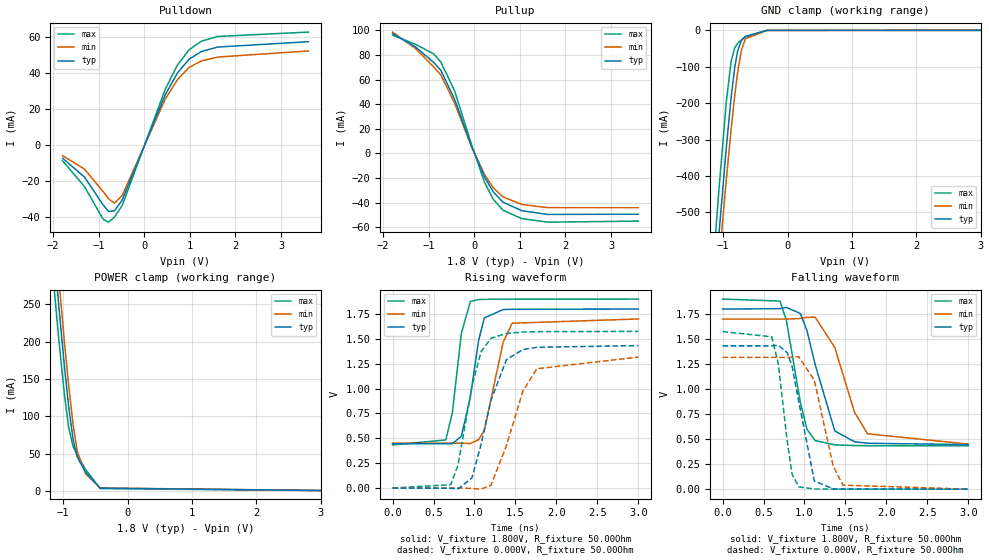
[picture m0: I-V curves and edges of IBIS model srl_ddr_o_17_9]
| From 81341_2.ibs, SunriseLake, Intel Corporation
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[Model]   srl_ddr_o_17_9
Model_type   Output
|Vinl = 650.000mV
|Vinh = 1.150V
Vmeas = 900.000mV
Vref = 900.000mV
Cref = 0.000F
Rref = 25.000Ohm
|   typ   min   max
C_comp   3.270pF   2.760pF   3.820pF
[Voltage Range]   1.800V   1.700V   1.900V
[Temperature Range]   60.0   110.0   -5.0
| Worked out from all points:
|   slope of the pulldown table from 0 to 0.27 V, typ, clamps not added: 15.8 ohm
|   slope of the pullup table from 0 to 0.27 V, typ, clamps not added: 12 ohm
|   GND clamp passes 1 mA (typ) near -0.41 V on its own axis
|   POWER clamp passes 1 mA (typ) near -0.35 V on its own axis
|   falling waveform, V_fixture 1.800V, R_fixture 50.00Ohm: 20-80 % time 245ps typ, 289ps min, 187ps max; typ from 1.8 V to 0.445 V
|   rising waveform, V_fixture 1.800V, R_fixture 50.00Ohm: 20-80 % time 151ps typ, 180ps min, 124ps max; typ from 0.445 V to 1.8 V
|   rising waveform, V_fixture 0.000V, R_fixture 50.00Ohm: 20-80 % time 259ps typ, 300ps min, 216ps max; typ from 0 V to 1.43 V
|   falling waveform, V_fixture 0.000V, R_fixture 50.00Ohm: 20-80 % time 175ps typ, 208ps min, 135ps max; typ from 1.43 V to 0 V
[Pulldown]
|   Voltage   I(typ)   I(min)   I(max)
-1.795V   -7.39mA    -5.975mA   -8.804mA
-1.315V   -17.83mA   -13.43mA   -23.1mA
-905mV    -33.28mA   -25.9mA    -41.28mA
-785mV    -36.99mA   -29.94mA   -42.92mA
-655mV    -36.57mA   -32.37mA   -40.11mA
-485mV    -30.56mA   -28mA      -33.56mA
455mV     27.6mA     25.21mA    30.63mA
725mV     39.87mA    36.24mA    44.26mA
980mV     47.53mA    42.95mA    52.77mA
1.25V     51.84mA    46.61mA    57.55mA
1.61V     54.32mA    48.78mA    60.21mA
3.6V      57.31mA    52.15mA    62.64mA
[GND Clamp]
|   Voltage   I(typ)   I(min)   I(max)
-1.795V   -2.204A    -2.188A    -2.214A
-1.165V   -777.4mA   -844.3mA   -670.1mA
-1.115V   -667.2mA   -740.5mA   -551.6mA
-1.07V    -569.4mA   -648mA     -447.4mA
-950mV    -320.2mA   -409.2mA   -194.4mA
-875mV    -182.6mA   -270.6mA   -84.27mA
-820mV    -101.8mA   -179.2mA   -47.93mA
-775mV    -57.03mA   -115.3mA   -35.76mA
-715mV    -27.68mA   -54mA      -25.89mA
-655mV    -16.67mA   -23.37mA   -18.05mA
-320mV    -113.3uA   -232.1uA   -24.81uA
3.6V      0A         0A         0A
[Pullup]
|   Voltage   I(typ)   I(min)   I(max)
-1.795V   97.29mA    98.53mA    96.09mA
-1.29V    86.5mA     85.19mA    88.61mA
-890mV    73.81mA    70.15mA    80.77mA
-735mV    67.5mA     63.79mA    74.17mA
-435mV    44.07mA    40.95mA    50.97mA
-65mV     6.251mA    5.666mA    7.632mA
225mV     -19.21mA   -17.2mA    -23.46mA
415mV     -31.18mA   -27.85mA   -37.27mA
630mV     -39.59mA   -35.33mA   -46.16mA
1.045V    -46.51mA   -41.44mA   -52.92mA
1.615V    -49.52mA   -44.04mA   -55.81mA
3.6V      -49.3mA    -44.06mA   -54.91mA
[POWER Clamp]
|   Voltage   I(typ)   I(min)   I(max)
-1.795V   1.029A     1.081A     953.5mA
-1.17V    349.9mA    389mA      300.6mA
-1.145V   324.6mA    363mA      276.3mA
-1.115V   294.4mA    332.1mA    247.5mA
-1.065V   245.4mA    281.6mA    201mA
-980mV    166.6mA    199.5mA    128.7mA
-915mV    113.2mA    141.8mA    85.32mA
-845mV    68.57mA    88.39mA    59.28mA
-780mV    45.17mA    52.7mA     47.98mA
-650mV    24.95mA    22.8mA     28.63mA
-425mV    3.719mA    3.953mA    3.218mA
3.6V      0A         0A         0A
[Ramp]
R_load = 50.00Ohm
|   typ   min   max
dV/dt_r   859.215mV/258.610ps 790.176mV/300.004ps 945.052mV/215.727ps
dV/dt_f   812.779mV/245.034ps 749.755mV/288.789ps 880.153mV/186.841ps
[Falling Waveform]
V_fixture = 1.800V
V_fixture_min = 1.700V
V_fixture_max = 1.900V
R_fixture = 50.00Ohm
|   Time   V(typ)   V(min)   V(max)
0s        1.8V       1.7V       1.9V
700ps     1.804V     1.7V       1.88V
780ps     1.816V     1.7V       1.683V
950ps     1.756V     1.706V     865.9mV
1.03ns    1.585V     1.717V     599.5mV
1.13ns    1.247V     1.719V     485.5mV
1.37ns    581.6mV    1.416V     443.2mV
1.61ns    473.6mV    770.5mV    435.9mV
1.77ns    459mV      553.3mV    434.3mV
3ns       445.4mV    450.4mV    433.1mV
[Rising Waveform]
V_fixture = 1.800V
V_fixture_min = 1.700V
V_fixture_max = 1.900V
R_fixture = 50.00Ohm
|   Time   V(typ)   V(min)   V(max)
0s        445.4mV    450.4mV    433.1mV
650ps     445.1mV    450.4mV    483.9mV
730ps     444.1mV    450.4mV    758.4mV
840ps     521.6mV    450.8mV    1.556V
950ps     917.5mV    447.1mV    1.876V
1.05ns    1.482V     486.9mV    1.895V
1.12ns    1.71V      578.7mV    1.897V
1.35ns    1.795V     1.466V     1.899V
1.46ns    1.797V     1.657V     1.899V
3ns       1.8V       1.7V       1.9V
[Rising Waveform]
V_fixture = 0.000V
V_fixture_min = 0.000V
V_fixture_max = 0.000V
R_fixture = 50.00Ohm
|   Time   V(typ)   V(min)   V(max)
0s        790.4nV    3.259uV    99.34nV
710ps     -2.464mV   -61.86uV   33.62mV
800ps     -9.696mV   558.6uV    235.1mV
970ps     102.9mV    -4.505mV   1.029V
1.08ns    437.7mV    -11.53mV   1.37V
1.2ns     879mV      26.84mV    1.505V
1.39ns    1.291V     426.3mV    1.554V
1.59ns    1.392V     971.7mV    1.568V
1.76ns    1.415V     1.199V     1.572V
3ns       1.432V     1.317V     1.575V
[Falling Waveform]
V_fixture = 0.000V
V_fixture_min = 0.000V
V_fixture_max = 0.000V
R_fixture = 50.00Ohm
|   Time   V(typ)   V(min)   V(max)
0s        1.432V     1.317V     1.575V
600ps     1.432V     1.317V     1.523V
680ps     1.438V     1.317V     1.255V
790ps     1.365V     1.317V     472.3mV
850ps     1.221V     1.317V     145.1mV
930ps     877.2mV    1.324V     22.83mV
1.12ns    81.62mV    1.089V     1.808mV
1.35ns    2.956mV    233.4mV    490.2uV
1.47ns    1.435mV    40.19mV    262.1uV
3ns       790.4nV    3.259uV    99.34nV
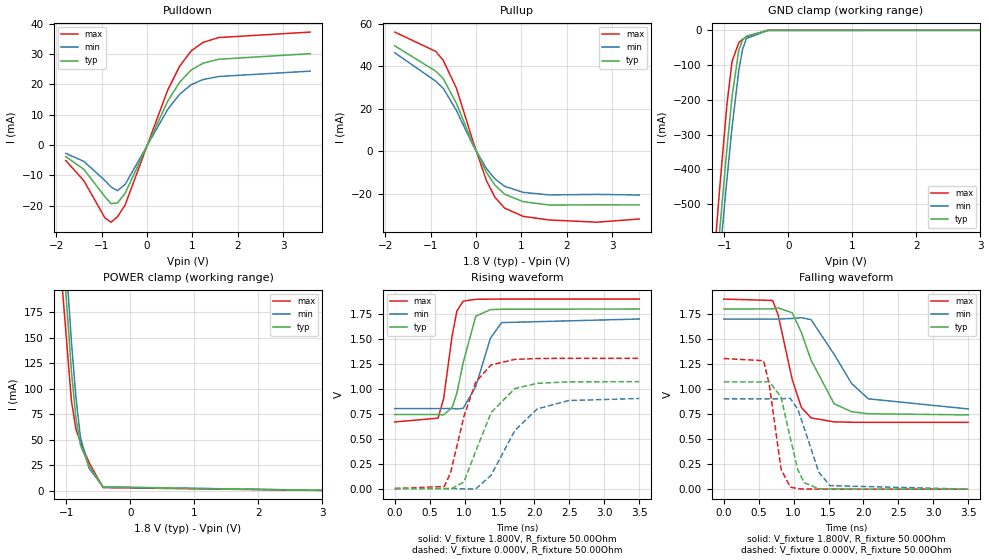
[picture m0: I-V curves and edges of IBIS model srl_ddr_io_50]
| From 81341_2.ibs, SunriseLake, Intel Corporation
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[Model]   srl_ddr_io_50
Model_type   I/O
Vinl = 650.000mV
Vinh = 1.150V
Vmeas = 900.000mV
Vref = 900.000mV
Cref = 0.000F
Rref = 25.000Ohm
|   typ   min   max
C_comp   3.270pF   2.760pF   3.820pF
[Voltage Range]   1.800V   1.700V   1.900V
[Temperature Range]   60.0   110.0   -5.0
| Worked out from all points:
|   slope of the pulldown table from 0 to 0.27 V, typ, clamps not added: 30.3 ohm
|   slope of the pullup table from 0 to 0.27 V, typ, clamps not added: 23.6 ohm
|   GND clamp passes 1 mA (typ) near -0.41 V on its own axis
|   POWER clamp passes 1 mA (typ) near -0.35 V on its own axis
|   falling waveform, V_fixture 1.800V, R_fixture 50.00Ohm: 20-80 % time 362ps typ, 474ps min, 244ps max; typ from 1.8 V to 0.742 V
|   rising waveform, V_fixture 1.800V, R_fixture 50.00Ohm: 20-80 % time 190ps typ, 238ps min, 146ps max; typ from 0.742 V to 1.8 V
|   rising waveform, V_fixture 0.000V, R_fixture 50.00Ohm: 20-80 % time 384ps typ, 472ps min, 307ps max; typ from 0 V to 1.07 V
|   falling waveform, V_fixture 0.000V, R_fixture 50.00Ohm: 20-80 % time 207ps typ, 253ps min, 152ps max; typ from 1.07 V to 0 V
[Pulldown]
|   Voltage   I(typ)   I(min)   I(max)
-1.795V   -3.817mA   -2.754mA   -5.119mA
-1.395V   -8.037mA   -5.398mA   -11.77mA
-930mV    -17.06mA   -11.73mA   -24.06mA
-795mV    -19.33mA   -13.86mA   -25.46mA
-655mV    -19.11mA   -15.06mA   -23.7mA
-485mV    -15.97mA   -13.01mA   -19.82mA
455mV     14.42mA    11.72mA    18.09mA
720mV     20.72mA    16.76mA    26mA
975mV     24.75mA    19.9mA     31.06mA
1.235V    26.97mA    21.58mA    33.84mA
1.58V     28.27mA    22.59mA    35.43mA
3.6V      30.11mA    24.35mA    37.23mA
[GND Clamp]
|   Voltage   I(typ)   I(min)   I(max)
-1.795V   -2.204A    -2.188A    -2.214A
-1.165V   -777.4mA   -844.3mA   -670.1mA
-1.115V   -667.2mA   -740.5mA   -551.6mA
-1.085V   -601.8mA   -678.7mA   -481.8mA
-1.07V    -569.4mA   -648mA     -447.4mA
-960mV    -340mA     -428.5mA   -213.1mA
-880mV    -191mA     -279.4mA   -89.47mA
-775mV    -57.03mA   -115.3mA   -35.77mA
-715mV    -27.68mA   -54mA      -25.89mA
-655mV    -16.67mA   -23.37mA   -18.05mA
-320mV    -113.3uA   -232.1uA   -24.87uA
3.6V      0A         0A         0A
[Pullup]
|   Voltage   I(typ)   I(min)   I(max)
-1.795V   49.54mA    46.27mA    55.99mA
-890mV    37.62mA    32.89mA    46.91mA
-725mV    34.13mA    29.6mA     42.71mA
-435mV    22.5mA     19.17mA    29.65mA
-65mV     3.192mA    2.652mA    4.441mA
225mV     -9.81mA    -8.044mA   -13.63mA
415mV     -15.92mA   -13.02mA   -21.63mA
630mV     -20.21mA   -16.5mA    -26.75mA
1.04V     -23.72mA   -19.33mA   -30.63mA
1.615V    -25.29mA   -20.55mA   -32.32mA
2.67V     -25.2mA    -20.29mA   -33.36mA
3.6V      -25.24mA   -20.58mA   -31.86mA
[POWER Clamp]
|   Voltage   I(typ)   I(min)   I(max)
-1.795V   1.029A     1.081A     953.6mA
-1.17V    349.9mA    389mA      300.6mA
-1.15V    329.6mA    368.2mA    281.1mA
-1.115V   294.4mA    332.1mA    247.5mA
-1.075V   255.1mA    291.6mA    210.2mA
-1.065V   245.4mA    281.6mA    201mA
-920mV    117mA      146mA      88.08mA
-850mV    71.14mA    91.78mA    60.48mA
-780mV    45.17mA    52.7mA     47.98mA
-645mV    24.26mA    22.12mA    27.81mA
-425mV    3.719mA    3.953mA    3.219mA
3.6V      0A         0A         0A
[Ramp]
R_load = 50.00Ohm
|   typ   min   max
dV/dt_r   643.471mV/383.726ps 541.699mV/472.086ps 783.618mV/306.825ps
dV/dt_f   634.624mV/361.956ps 538.793mV/473.312ps 739.369mV/244.332ps
[Falling Waveform]
V_fixture = 1.800V
V_fixture_min = 1.700V
V_fixture_max = 1.900V
R_fixture = 50.00Ohm
|   Time   V(typ)   V(min)   V(max)
0s        1.8V       1.7V       1.9V
700ps     1.802V     1.7V       1.886V
780ps     1.811V     1.7V       1.736V
980ps     1.763V     1.706V     1.095V
1.11ns    1.568V     1.714V     817.7mV
1.25ns    1.289V     1.694V     712mV
1.58ns    853.6mV    1.348V     672.4mV
1.83ns    774.1mV    1.056V     668.8mV
2.07ns    753.8mV    902.8mV    668mV
3.5ns     742.3mV    802mV      667.7mV
[Rising Waveform]
V_fixture = 1.800V
V_fixture_min = 1.700V
V_fixture_max = 1.900V
R_fixture = 50.00Ohm
|   Time   V(typ)   V(min)   V(max)
0s        742.3mV    802mV      667.7mV
620ps     742.6mV    802mV      706mV
700ps     737.8mV    802mV      903.3mV
820ps     812.4mV    802.3mV    1.526V
890ps     958.8mV    798.1mV    1.782V
980ps     1.264V     805.3mV    1.879V
1.16ns    1.728V     1.023V     1.898V
1.37ns    1.794V     1.508V     1.899V
1.53ns    1.798V     1.664V     1.9V
3.5ns     1.8V       1.7V       1.9V
[Rising Waveform]
V_fixture = 0.000V
V_fixture_min = 0.000V
V_fixture_max = 0.000V
R_fixture = 50.00Ohm
|   Time   V(typ)   V(min)   V(max)
0s        974.3nV    5.039uV    210.9nV
710ps     -944.1uV   -31.06uV   21.18mV
800ps     -6.044mV   276.8uV    160.1mV
990ps     66.47mV    -3.017mV   723.4mV
1.16ns    375.6mV    -4.234mV   1.068V
1.38ns    762.3mV    135mV      1.24V
1.72ns    1.003V     582.5mV    1.295V
2.04ns    1.055V     798.8mV    1.304V
2.49ns    1.07V      882.7mV    1.306V
3.5ns     1.072V     902.8mV    1.306V
[Falling Waveform]
V_fixture = 0.000V
V_fixture_min = 0.000V
V_fixture_max = 0.000V
R_fixture = 50.00Ohm
|   Time   V(typ)   V(min)   V(max)
0s        1.072V     902.8mV    1.306V
570ps     1.072V     902.8mV    1.284V
650ps     1.076V     902.9mV    1.052V
820ps     920.3mV    902.6mV    200.8mV
950ps     517.1mV    909mV      21.7mV
1.06ns    194.1mV    798.7mV    4.04mV
1.15ns    64.65mV    613mV      1.479mV
1.36ns    4.911mV    169.8mV    324.4uV
1.52ns    1.313mV    35.31mV    125uV
3.5ns     974.3nV    5.039uV    210.9nV
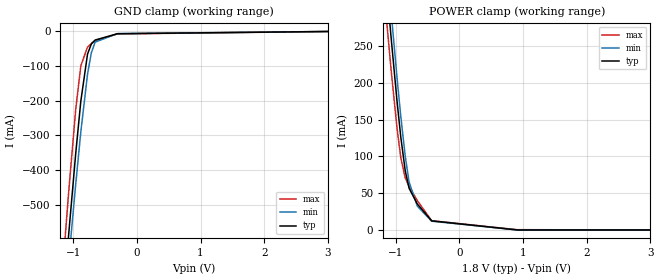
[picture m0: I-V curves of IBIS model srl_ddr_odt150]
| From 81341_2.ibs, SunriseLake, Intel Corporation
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[Model]   srl_ddr_odt150
Model_type   Input
Vinl = 650.000mV
Vinh = 1.150V
|   typ   min   max
C_comp   3.270pF   2.760pF   3.820pF
[Voltage Range]   1.800V   1.700V   1.900V
[Temperature Range]   60.0   110.0   -5.0
[GND Clamp]
|   Voltage   I(typ)   I(min)   I(max)
-1.795V   -2.233A    -2.215A    -2.246A
-1.165V   -793.6mA   -859.9mA   -686.7mA
-1.12V    -693.4mA   -765.5mA   -578.8mA
-1.09V    -627.3mA   -703.1mA   -508mA
-1.07V    -583.6mA   -661.8mA   -461.6mA
-960mV    -351.9mA   -440.3mA   -224.8mA
-880mV    -201.5mA   -289.9mA   -100mA
-775mV    -66.43mA   -124.3mA   -45.89mA
-715mV    -36.89mA   -62.53mA   -35.82mA
-655mV    -25.72mA   -31.71mA   -27.78mA
-305mV    -7.618mA   -7.221mA   -8.084mA
3.599V    0A         0A         0A
[POWER Clamp]
|   Voltage   I(typ)   I(min)   I(max)
-1.795V   1.039A     1.09A      965mA
-1.145V   334mA      371.3mA    286.8mA
-1.095V   284mA      320.1mA    239.2mA
-1.065V   254.8mA    289.9mA    211.5mA
-980mV    175.9mA    207.8mA    139.1mA
-920mV    126.3mA    154.3mA    98.3mA
-850mV    80.32mA    100.1mA    70.56mA
-790mV    56.78mA    65.34mA    59.38mA
-660mV    35.17mA    32.28mA    39.87mA
-435mV    12.37mA    11.93mA    12.6mA
910mV     0A         0A         374.1uA
3.599V    0A         0A         0A
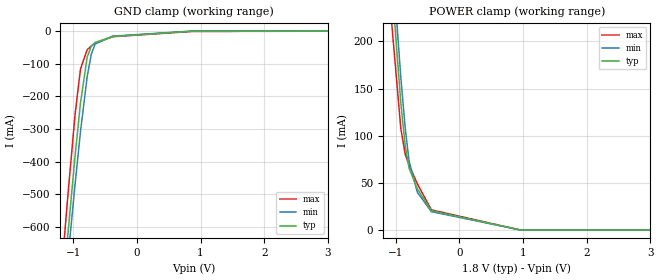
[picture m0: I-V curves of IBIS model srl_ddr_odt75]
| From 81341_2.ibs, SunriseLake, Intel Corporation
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[Model]   srl_ddr_odt75
Model_type   Input
Vinl = 650.000mV
Vinh = 1.150V
|   typ   min   max
C_comp   3.270pF   2.760pF   3.820pF
[Voltage Range]   1.800V   1.700V   1.900V
[Temperature Range]   60.0   110.0   -5.0
[GND Clamp]
|   Voltage   I(typ)   I(min)   I(max)
-1.795V   -2.243A    -2.223A    -2.258A
-1.16V    -792mA     -857.8mA   -685.1mA
-1.115V   -691.9mA   -763.5mA   -577.3mA
-1.085V   -625.8mA   -701.2mA   -506.6mA
-970mV    -381.4mA   -468.1mA   -254.4mA
-885mV    -219.3mA   -307mA     -115.7mA
-780mV    -79.49mA   -138.9mA   -56.89mA
-715mV    -45.99mA   -70.56mA   -45.63mA
-655mV    -34.66mA   -39.69mA   -37.4mA
-380mV    -16.42mA   -15.39mA   -17.2mA
855mV     -645.3uA   0A         -1.218mA
3.599V    0A         0A         0A
[POWER Clamp]
|   Voltage   I(typ)   I(min)   I(max)
-1.795V   1.048A     1.098A     975.4mA
-1.165V   363.3mA    400.2mA    316.1mA
-1.145V   342.9mA    379.4mA    296.6mA
-1.11V    307.8mA    343.4mA    263.1mA
-1.065V   263.7mA    298mA      221.2mA
-920mV    135.1mA    162.3mA    107.9mA
-850mV    89.06mA    108mA      80.12mA
-790mV    65.47mA    73.2mA     68.82mA
-660mV    43.61mA    39.99mA    48.97mA
-440mV    20.49mA    19.41mA    21.34mA
955mV     0A         0A         0A
3.599V    0A         0A         0A
